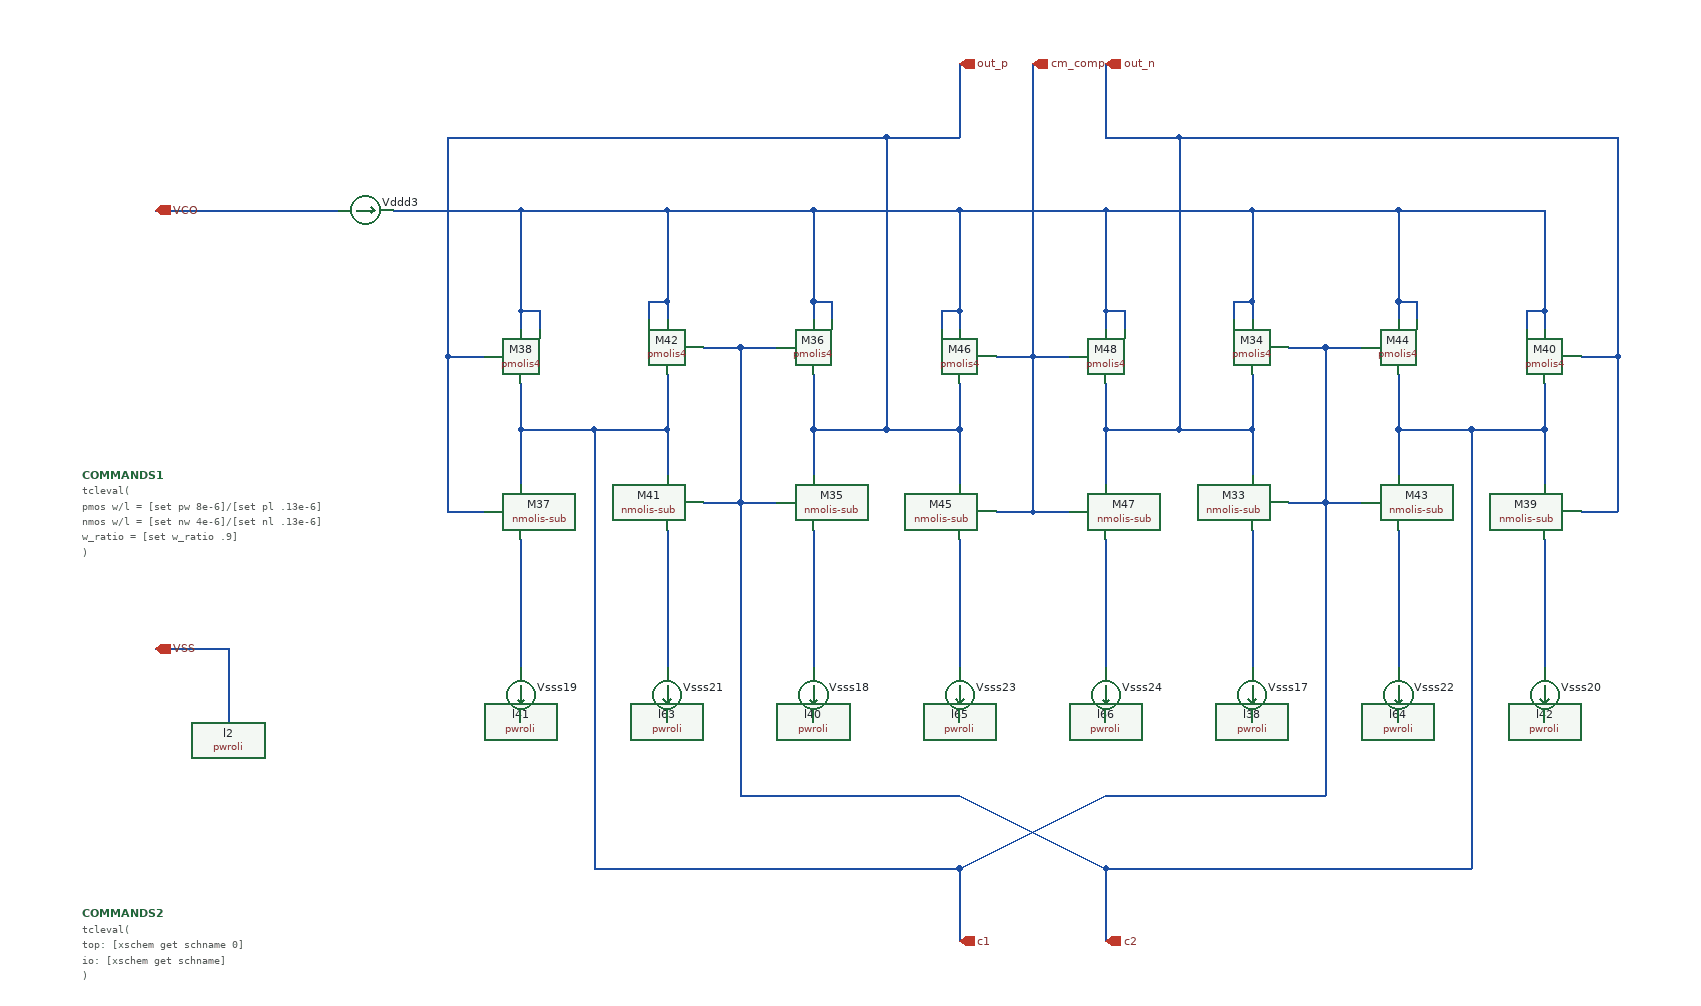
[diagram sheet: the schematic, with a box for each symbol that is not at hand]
v {xschem version=3.4.6 file_version=1.2
*
* This file is part of XSCHEM,
* a schematic capture and Spice/Vhdl/Verilog netlisting tool for circuit
* simulation.
* Copyright (C) 1998-2023 Stefan Frederik Schippers
*
* This program is free software; you can redistribute it and/or modify
* it under the terms of the GNU General Public License as published by
* the Free Software Foundation; either version 2 of the License, or
* (at your option) any later version.
*
* This program is distributed in the hope that it will be useful,
* but WITHOUT ANY WARRANTY; without even the implied warranty of
* MERCHANTABILITY or FITNESS FOR A PARTICULAR PURPOSE.  See the
* GNU General Public License for more details.
*
* You should have received a copy of the GNU General Public License
* along with this program; if not, write to the Free Software
* Foundation, Inc., 51 Franklin Street, Fifth Floor, Boston, MA 02110-1301 USA
}
G {}
K {}
V {}
S {}
E {}
N 1440 -860 1440 -840 {lab=#net1}
N 1420 -860 1420 -840 {lab=#net1}
N 1420 -860 1440 -860 {lab=#net1}
N 1440 -610 1440 -460 {lab=#net2}
N 1440 -960 1440 -860 {lab=#net1}
N 1480 -810 1520 -810 {lab=c1}
N 1480 -640 1520 -640 {lab=c1}
N 960 -860 960 -840 {lab=#net1}
N 980 -860 980 -840 {lab=#net1}
N 960 -860 980 -860 {lab=#net1}
N 960 -610 960 -460 {lab=#net3}
N 960 -960 960 -860 {lab=#net1}
N 880 -810 920 -810 {lab=c2}
N 880 -640 920 -640 {lab=c2}
N 640 -850 640 -830 {lab=#net1}
N 660 -850 660 -830 {lab=#net1}
N 640 -850 660 -850 {lab=#net1}
N 640 -600 640 -460 {lab=#net4}
N 640 -960 640 -850 {lab=#net1}
N 560 -800 600 -800 {lab=out_p}
N 560 -630 600 -630 {lab=out_p}
N 960 -960 1120 -960 {lab=#net1}
N 1760 -850 1760 -830 {lab=#net1}
N 1740 -850 1740 -830 {lab=#net1}
N 1740 -850 1760 -850 {lab=#net1}
N 1760 -600 1760 -460 {lab=#net5}
N 1760 -960 1760 -850 {lab=#net1}
N 1800 -800 1840 -800 {lab=out_n}
N 1800 -630 1840 -630 {lab=out_n}
N 1840 -1040 1840 -800 {lab=out_n}
N 1120 -240 1280 -320 {lab=c1}
N 1120 -320 1280 -240 {lab=c2}
N 800 -860 800 -840 {lab=#net1}
N 780 -860 780 -840 {lab=#net1}
N 780 -860 800 -860 {lab=#net1}
N 800 -610 800 -460 {lab=#net6}
N 800 -960 800 -860 {lab=#net1}
N 840 -810 880 -810 {lab=c2}
N 840 -640 880 -640 {lab=c2}
N 800 -960 960 -960 {lab=#net1}
N 1600 -860 1600 -840 {lab=#net1}
N 1620 -860 1620 -840 {lab=#net1}
N 1600 -860 1620 -860 {lab=#net1}
N 1600 -610 1600 -460 {lab=#net7}
N 1600 -960 1600 -860 {lab=#net1}
N 1520 -810 1560 -810 {lab=c1}
N 1520 -640 1560 -640 {lab=c1}
N 1440 -960 1600 -960 {lab=#net1}
N 640 -720 640 -660 {lab=c1}
N 1600 -720 1600 -670 {lab=c2}
N 1760 -720 1760 -660 {lab=c2}
N 1440 -720 1440 -670 {lab=out_n}
N 1840 -800 1840 -630 {lab=out_n}
N 960 -780 960 -720 {lab=out_p}
N 560 -800 560 -630 {lab=out_p}
N 1280 -960 1440 -960 {lab=#net1}
N 560 -1040 560 -800 {lab=out_p}
N 1280 -240 1680 -240 {lab=c2}
N 1280 -320 1520 -320 {lab=c1}
N 1120 -850 1120 -830 {lab=#net1}
N 1100 -850 1100 -830 {lab=#net1}
N 1100 -850 1120 -850 {lab=#net1}
N 1120 -600 1120 -460 {lab=#net8}
N 1120 -960 1120 -850 {lab=#net1}
N 1280 -850 1280 -830 {lab=#net1}
N 1300 -850 1300 -830 {lab=#net1}
N 1280 -850 1300 -850 {lab=#net1}
N 1280 -600 1280 -460 {lab=#net9}
N 1280 -960 1280 -850 {lab=#net1}
N 1120 -960 1280 -960 {lab=#net1}
N 1160 -630 1200 -630 {lab=cm_comp}
N 1160 -800 1200 -800 {lab=cm_comp}
N 1200 -630 1240 -630 {lab=cm_comp}
N 1200 -800 1240 -800 {lab=cm_comp}
N 960 -720 960 -670 {lab=out_p}
N 1280 -770 1280 -720 {lab=out_n}
N 1280 -720 1280 -660 {lab=out_n}
N 1120 -770 1120 -720 {lab=out_p}
N 1120 -720 1120 -660 {lab=out_p}
N 880 -810 880 -640 {lab=c2}
N 1520 -810 1520 -640 {lab=c1}
N 800 -720 800 -670 {lab=c1}
N 1040 -720 1120 -720 {lab=out_p}
N 1360 -720 1440 -720 {lab=out_n}
N 1440 -780 1440 -720 {lab=out_n}
N 1600 -960 1760 -960 {lab=#net1}
N 640 -960 800 -960 {lab=#net1}
N 720 -720 800 -720 {lab=c1}
N 640 -770 640 -720 {lab=c1}
N 800 -780 800 -720 {lab=c1}
N 1680 -720 1760 -720 {lab=c2}
N 1600 -780 1600 -720 {lab=c2}
N 1760 -770 1760 -720 {lab=c2}
N 880 -640 880 -320 {lab=c2}
N 880 -320 1120 -320 {lab=c2}
N 720 -720 720 -240 {lab=c1}
N 640 -720 720 -720 {lab=c1}
N 720 -240 1120 -240 {lab=c1}
N 1680 -720 1680 -240 {lab=c2}
N 1600 -720 1680 -720 {lab=c2}
N 1520 -640 1520 -320 {lab=c1}
N 1040 -1040 1120 -1040 {lab=out_p}
N 1120 -1120 1120 -1040 {lab=out_p}
N 1200 -1120 1200 -800 {lab=cm_comp}
N 1280 -1120 1280 -1040 {lab=out_n}
N 1360 -1040 1840 -1040 {lab=out_n}
N 1360 -1040 1360 -720 {lab=out_n}
N 1280 -1040 1360 -1040 {lab=out_n}
N 1280 -720 1360 -720 {lab=out_n}
N 1040 -1040 1040 -720 {lab=out_p}
N 560 -1040 1040 -1040 {lab=out_p}
N 960 -720 1040 -720 {lab=out_p}
N 1120 -240 1120 -160 {lab=c1}
N 1280 -240 1280 -160 {lab=c2}
N 1200 -800 1200 -630 {lab=cm_comp}
N 240 -480 320 -480 {
lab=VSS}
N 320 -480 320 -400 {
lab=VSS}
N 240 -960 440 -960 {lab=VCO}
N 500 -960 640 -960 {lab=#net1}
C {title.sym} 160 -30 0 0 {name=l1 author="om"  net_name=true}
C {pwroli.sym} 1440 -400 0 1 {name=l38 lab=VSS}
C {ammeter.sym} 1440 -430 0 1 {name=Vsss17 
savecurrent=true
lvs_ignore=short}
C {ammeter.sym} 470 -960 3 1 {name=Vddd3
savecurrent=true
lvs_ignore=short}
C {nmolis-sub.sym} 1460 -640 0 1 {name=M33
w="tcleval([string map \{\{$\} \{\}\} [ev \{$w_ratio * $nw\}]])"
l="tcleval([string map \{\{$\} \{\}\} [ev \{$nl\}]])"
ng=1
m=1

model=sg13_lv_nmos
spiceprefix=X
w0=3u
l0=0.13u
rfmode="tcleval($mos_rf_mode)"}
C {pmolis4.sym} 1460 -810 0 1 {name=M34
w="tcleval([string map \{\{$\} \{\}\} [ev \{$w_ratio * $pw\}]])"
l="tcleval([string map \{\{$\} \{\}\} [ev \{$pl\}]])"
ng=1
m=1
substrate=VDD
model=sg13_lv_pmos
spiceprefix=X
w0=10u
l0=.13u
rfmode="tcleval($mos_rf_mode)"}
C {pwroli.sym} 960 -400 0 0 {name=l40 lab=VSS}
C {ammeter.sym} 960 -430 0 0 {name=Vsss18 
savecurrent=true
lvs_ignore=short}
C {nmolis-sub.sym} 940 -640 0 0 {name=M35
w="tcleval([string map \{\{$\} \{\}\} [ev \{$w_ratio * $nw\}]])"
l="tcleval([string map \{\{$\} \{\}\} [ev \{$nl\}]])"
ng=1
m=1

model=sg13_lv_nmos
spiceprefix=X
w0=3u
l0=0.13u
rfmode="tcleval($mos_rf_mode)"}
C {pmolis4.sym} 940 -810 0 0 {name=M36
w="tcleval([string map \{\{$\} \{\}\} [ev \{$w_ratio * $pw\}]])"
l="tcleval([string map \{\{$\} \{\}\} [ev \{$pl\}]])"
ng=1
m=1
substrate=VDD
model=sg13_lv_pmos
spiceprefix=X
w0=10u
l0=.13u
rfmode="tcleval($mos_rf_mode)"}
C {pwroli.sym} 640 -400 0 0 {name=l41 lab=VSS}
C {ammeter.sym} 640 -430 0 0 {name=Vsss19 
savecurrent=true
lvs_ignore=short}
C {nmolis-sub.sym} 620 -630 0 0 {name=M37
w="tcleval([string map \{\{$\} \{\}\} [ev \{$nw\}]])"
l="tcleval([string map \{\{$\} \{\}\} [ev \{$nl\}]])"
ng=1
m=1

model=sg13_lv_nmos
spiceprefix=X
w0=3u
l0=0.13u
rfmode="tcleval($mos_rf_mode)"}
C {pmolis4.sym} 620 -800 0 0 {name=M38
w="tcleval([string map \{\{$\} \{\}\} [ev \{$pw\}]])"
l="tcleval([string map \{\{$\} \{\}\} [ev \{$pl\}]])"
ng=1
m=1
substrate=VDD
model=sg13_lv_pmos
spiceprefix=X
w0=10u
l0=.13u
rfmode="tcleval($mos_rf_mode)"}
C {pwroli.sym} 1760 -400 0 1 {name=l42 lab=VSS}
C {ammeter.sym} 1760 -430 0 1 {name=Vsss20 
savecurrent=true
lvs_ignore=short}
C {nmolis-sub.sym} 1780 -630 0 1 {name=M39
w="tcleval([string map \{\{$\} \{\}\} [ev \{$nw\}]])"
l="tcleval([string map \{\{$\} \{\}\} [ev \{$nl\}]])"
ng=1
m=1

model=sg13_lv_nmos
spiceprefix=X
w0=3u
l0=0.13u
rfmode="tcleval($mos_rf_mode)"}
C {pmolis4.sym} 1780 -800 0 1 {name=M40
w="tcleval([string map \{\{$\} \{\}\} [ev \{$pw\}]])"
l="tcleval([string map \{\{$\} \{\}\} [ev \{$pl\}]])"
ng=1
m=1
substrate=VDD
model=sg13_lv_pmos
spiceprefix=X
w0=10u
l0=.13u
rfmode="tcleval($mos_rf_mode)"}
C {pwroli.sym} 800 -400 0 1 {name=l63 lab=VSS}
C {ammeter.sym} 800 -430 0 1 {name=Vsss21 
savecurrent=true
lvs_ignore=short}
C {nmolis-sub.sym} 820 -640 0 1 {name=M41
w="tcleval([string map \{\{$\} \{\}\} [ev \{$nw\}]])"
l="tcleval([string map \{\{$\} \{\}\} [ev \{$nl\}]])"
ng=1
m=1

model=sg13_lv_nmos
spiceprefix=X
w0=3u
l0=0.13u
rfmode="tcleval($mos_rf_mode)"}
C {pmolis4.sym} 820 -810 0 1 {name=M42
w="tcleval([string map \{\{$\} \{\}\} [ev \{$pw\}]])"
l="tcleval([string map \{\{$\} \{\}\} [ev \{$pl\}]])"
ng=1
m=1
substrate=VDD
model=sg13_lv_pmos
spiceprefix=X
w0=10u
l0=.13u
rfmode="tcleval($mos_rf_mode)"}
C {pwroli.sym} 1600 -400 0 0 {name=l64 lab=VSS}
C {ammeter.sym} 1600 -430 0 0 {name=Vsss22 
savecurrent=true
lvs_ignore=short}
C {nmolis-sub.sym} 1580 -640 0 0 {name=M43
w="tcleval([string map \{\{$\} \{\}\} [ev \{$nw\}]])"
l="tcleval([string map \{\{$\} \{\}\} [ev \{$nl\}]])"
ng=1
m=1

model=sg13_lv_nmos
spiceprefix=X
w0=3u
l0=0.13u
rfmode="tcleval($mos_rf_mode)"}
C {pmolis4.sym} 1580 -810 0 0 {name=M44
w="tcleval([string map \{\{$\} \{\}\} [ev \{$pw\}]])"
l="tcleval([string map \{\{$\} \{\}\} [ev \{$pl\}]])"
ng=1
m=1
substrate=VDD
model=sg13_lv_pmos
spiceprefix=X
w0=10u
l0=.13u
rfmode="tcleval($mos_rf_mode)"}
C {pwroli.sym} 1120 -400 0 1 {name=l65 lab=VSS}
C {ammeter.sym} 1120 -430 0 1 {name=Vsss23 
savecurrent=true
lvs_ignore=short}
C {nmolis-sub.sym} 1140 -630 0 1 {name=M45
w="tcleval([string map \{\{$\} \{\}\} [ev \{$nw\}]])"
l="tcleval([string map \{\{$\} \{\}\} [ev \{$nl\}]])"
ng=1
m=1

model=sg13_lv_nmos
spiceprefix=X
w0=3u
l0=0.13u
rfmode="tcleval($mos_rf_mode)"}
C {pmolis4.sym} 1140 -800 0 1 {name=M46
w="tcleval([string map \{\{$\} \{\}\} [ev \{$pw\}]])"
l="tcleval([string map \{\{$\} \{\}\} [ev \{$pl\}]])"
ng=1
m=1
substrate=VDD
model=sg13_lv_pmos
spiceprefix=X
w0=10u
l0=.13u
rfmode="tcleval($mos_rf_mode)"}
C {pwroli.sym} 1280 -400 0 0 {name=l66 lab=VSS}
C {ammeter.sym} 1280 -430 0 0 {name=Vsss24 
savecurrent=true
lvs_ignore=short}
C {nmolis-sub.sym} 1260 -630 0 0 {name=M47
w="tcleval([string map \{\{$\} \{\}\} [ev \{$nw\}]])"
l="tcleval([string map \{\{$\} \{\}\} [ev \{$nl\}]])"
ng=1
m=1

model=sg13_lv_nmos
spiceprefix=X
w0=3u
l0=0.13u
rfmode="tcleval($mos_rf_mode)"}
C {pmolis4.sym} 1260 -800 0 0 {name=M48
w="tcleval([string map \{\{$\} \{\}\} [ev \{$pw\}]])"
l="tcleval([string map \{\{$\} \{\}\} [ev \{$pl\}]])"
ng=1
m=1
substrate=VDD
model=sg13_lv_pmos
spiceprefix=X
w0=10u
l0=.13u
rfmode="tcleval($mos_rf_mode)"}
C {iopin.sym} 240 -480 0 1 {name=p8 lab=VSS

}
C {pwroli.sym} 320 -400 0 0 {name=l2 lab=VSS}
C {iopin.sym} 240 -960 0 1 {name=p9 lab=VCO}
C {launcher.sym} 220 -880 0 0 {name=h1
descr="write LVS netlist"
tclcommand="
	xschem set netlist_type spice
	set lvs_ignore 1
	set lvs_netlist 1
	set spiceprefix 0
	set last_local_netlist_dir $local_netlist_dir
	set local_netlist_dir 0
	xschem netlist [xschem get current_name].cdl
	set local_netlist_dir $last_local_netlist_dir

"
}
C {simulator_commands_shown.sym} 160 -190 0 0 {name=COMMANDS2
simulator=none
only_toplevel=false 

value="tcleval(
top: [xschem get schname 0]
io:  [xschem get schname]

)"}
C {simulator_commands_shown.sym} 160 -670 0 0 {name=COMMANDS1
simulator=none
only_toplevel=true 

value="tcleval(

pmos w/l = [set pw 8e-6]/[set pl .13e-6]
nmos w/l = [set nw 4e-6]/[set nl .13e-6]

w_ratio = [set w_ratio .9]

)"}
C {launcher.sym} 220 -840 0 0 {name=h2
descr="load OP from TOP"
tclcommand="
	xschem annotate_op $\{netlist_dir\}/[file rootname [file tail [xschem get schname 0]]].raw 0;
	xschem load_raw $\{netlist_dir\}/[file rootname [file tail [xschem get schname 0]]]_dc.raw 0;

"
}
C {iopin.sym} 1120 -1120 1 1 {name=p1 lab=out_p}
C {iopin.sym} 1200 -1120 1 1 {name=p2 lab=cm_comp}
C {iopin.sym} 1280 -1120 1 1 {name=p3 lab=out_n}
C {iopin.sym} 1120 -160 3 1 {name=p4 lab=c1}
C {iopin.sym} 1280 -160 3 1 {name=p5 lab=c2}
C {ngspice_probe.sym} 1120 -1040 0 0 {name=r3}
C {ngspice_probe.sym} 1280 -1040 0 0 {name=r1}
C {ngspice_probe.sym} 1200 -1040 0 0 {name=r2}
C {ngspice_probe.sym} 720 -720 0 0 {name=r4}
C {ngspice_probe.sym} 1040 -720 0 0 {name=r5}
C {ngspice_probe.sym} 1360 -720 0 0 {name=r6}
C {ngspice_probe.sym} 1680 -720 0 0 {name=r7}
C {ngspice_probe.sym} 1520 -720 0 0 {name=r8}
C {ngspice_probe.sym} 1200 -720 0 0 {name=r9}
C {ngspice_probe.sym} 880 -720 0 0 {name=r10}
C {ngspice_probe.sym} 560 -720 0 0 {name=r11}
C {ngspice_probe.sym} 1840 -720 0 0 {name=r12}
C {ngspice_probe.sym} 640 -960 0 0 {name=r13}
